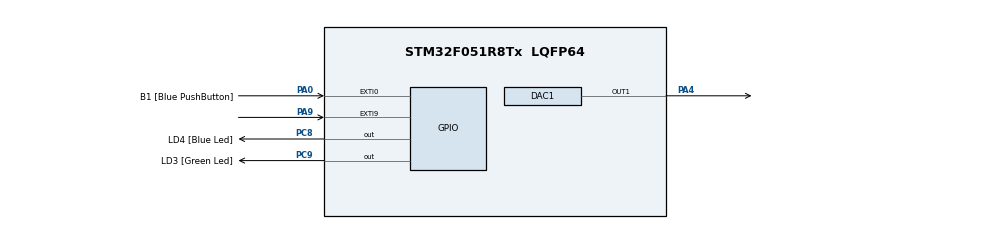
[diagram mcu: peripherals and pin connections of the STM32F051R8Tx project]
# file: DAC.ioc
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DAC1.DAC_Trigger=DAC_TRIGGER_SOFTWARE
Mcu.Family=STM32F0
Mcu.Name=STM32F051R8Tx
Mcu.Package=LQFP64
PA0.GPIO_Label=B1 [Blue PushButton]
PA0.GPIO_ModeDefaultEXTI=GPIO_MODE_EVT_RISING
PA0.Signal=GPXTI0
PA13.GPIO_Label=SWDIO
PA13.Signal=SYS_SWDIO
PA14.GPIO_Label=SWCLK
PA14.Signal=SYS_SWCLK
PA4.Signal=COMP_DAC11_group
PA9.Signal=GPXTI9
PC8.GPIO_Label=LD4 [Blue Led]
PC8.Signal=GPIO_Output
PC9.GPIO_Label=LD3 [Green Led]
PC9.Signal=GPIO_Output
ProjectManager.HeapSize=0x200
ProjectManager.StackSize=0x400
ProjectManager.TargetToolchain=MDK-ARM V5
RCC.AHBFreq_Value=48000000
RCC.APB1CLKDivider=RCC_HCLK_DIV2
RCC.APB1Freq_Value=24000000
RCC.APB1TimFreq_Value=48000000
RCC.HCLKFreq_Value=48000000
RCC.PLLMUL=RCC_PLL_MUL12
RCC.SYSCLKFreq_VALUE=48000000
RCC.SYSCLKSource=RCC_SYSCLKSOURCE_PLLCLK
SH.COMP_DAC11_group.0=DAC1_OUT1,DAC_OUT1
board=STM32F0DISCOVERY

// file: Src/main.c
/**
  ******************************************************************************
  * File Name          : main.c
  * Description        : Main program body
  ******************************************************************************
  ** This notice applies to any and all portions of this file
  * that are not between comment pairs USER CODE BEGIN and
  * USER CODE END. Other portions of this file, whether
  * inserted by the user or by software development tools
  * are owned by their respective copyright owners.
  *
  * COPYRIGHT(c) 2018 STMicroelectronics
  *
  * Redistribution and use in source and binary forms, with or without modification,
  * are permitted provided that the following conditions are met:
  *   1. Redistributions of source code must retain the above copyright notice,
  *      this list of conditions and the following disclaimer.
  *   2. Redistributions in binary form must reproduce the above copyright notice,
  *      this list of conditions and the following disclaimer in the documentation
  *      and/or other materials provided with the distribution.
  *   3. Neither the name of STMicroelectronics nor the names of its contributors
  *      may be used to endorse or promote products derived from this software
  *      without specific prior written permission.
  *
  * THIS SOFTWARE IS PROVIDED BY THE COPYRIGHT HOLDERS AND CONTRIBUTORS "AS IS"
  * AND ANY EXPRESS OR IMPLIED WARRANTIES, INCLUDING, BUT NOT LIMITED TO, THE
  * IMPLIED WARRANTIES OF MERCHANTABILITY AND FITNESS FOR A PARTICULAR PURPOSE ARE
  * DISCLAIMED. IN NO EVENT SHALL THE COPYRIGHT HOLDER OR CONTRIBUTORS BE LIABLE
  * FOR ANY DIRECT, INDIRECT, INCIDENTAL, SPECIAL, EXEMPLARY, OR CONSEQUENTIAL
  * DAMAGES (INCLUDING, BUT NOT LIMITED TO, PROCUREMENT OF SUBSTITUTE GOODS OR
  * SERVICES; LOSS OF USE, DATA, OR PROFITS; OR BUSINESS INTERRUPTION) HOWEVER
  * CAUSED AND ON ANY THEORY OF LIABILITY, WHETHER IN CONTRACT, STRICT LIABILITY,
  * OR TORT (INCLUDING NEGLIGENCE OR OTHERWISE) ARISING IN ANY WAY OUT OF THE USE
  * OF THIS SOFTWARE, EVEN IF ADVISED OF THE POSSIBILITY OF SUCH DAMAGE.
  *
  ******************************************************************************
  */

#include "main.h"
#include "stm32f0xx_hal.h"

DAC_HandleTypeDef hdac1;

/* USER CODE BEGIN PV */
/* Private variables ---------------------------------------------------------*/

/* USER CODE END PV */

void SystemClock_Config(void);
static void MX_GPIO_Init(void);
static void MX_DAC1_Init(void);

/* USER CODE BEGIN PFP */
/* Private function prototypes -----------------------------------------------*/

/* USER CODE END PFP */

int main(void)
{

  /* MCU Configuration----------------------------------------------------------*/

  /* Reset of all peripherals, Initializes the Flash interface and the Systick. */
  HAL_Init();

  /* Configure the system clock */
  SystemClock_Config();

  /* Initialize all configured peripherals */
  MX_GPIO_Init();
  MX_DAC1_Init();

  /* Infinite loop */
  while (1)
  {
		for(int i=0; i< 2048; i++){
			HAL_DAC_Start(&hdac1, DAC_CHANNEL_1);
			HAL_DAC_SetValue(&hdac1, DAC_CHANNEL_1, DAC_ALIGN_12B_R, (i*2)+1);
			//HAL_DAC_Stop(&hdac1, DAC_CHANNEL_1);
		}
		for(int i=2048; i > 0; i--){
			HAL_DAC_Start(&hdac1, DAC_CHANNEL_1);
			HAL_DAC_SetValue(&hdac1, DAC_CHANNEL_1, DAC_ALIGN_12B_R, (i*2)+1);
			//HAL_DAC_Stop(&hdac1, DAC_CHANNEL_1);
		}
		HAL_GPIO_TogglePin(GPIOC, GPIO_PIN_8);
		//HAL_DACEx_TriangleWaveGenerate(&hdac1, DAC_CHANNEL_1, DAC_ALIGN_12B_R);
  }

}

/** System Clock Configuration
*/
void SystemClock_Config(void)
{

  RCC_OscInitTypeDef RCC_OscInitStruct;
  RCC_ClkInitTypeDef RCC_ClkInitStruct;

    /**Initializes the CPU, AHB and APB busses clocks
    */
  RCC_OscInitStruct.OscillatorType = RCC_OSCILLATORTYPE_HSI;
  RCC_OscInitStruct.HSIState = RCC_HSI_ON;
  RCC_OscInitStruct.HSICalibrationValue = 16;
  RCC_OscInitStruct.PLL.PLLState = RCC_PLL_ON;
  RCC_OscInitStruct.PLL.PLLSource = RCC_PLLSOURCE_HSI;
  RCC_OscInitStruct.PLL.PLLMUL = RCC_PLL_MUL12;
  RCC_OscInitStruct.PLL.PREDIV = RCC_PREDIV_DIV1;
  if (HAL_RCC_OscConfig(&RCC_OscInitStruct) != HAL_OK)
  {
    _Error_Handler(__FILE__, __LINE__);
  }

    /**Initializes the CPU, AHB and APB busses clocks
    */
  RCC_ClkInitStruct.ClockType = RCC_CLOCKTYPE_HCLK|RCC_CLOCKTYPE_SYSCLK
                              |RCC_CLOCKTYPE_PCLK1;
  RCC_ClkInitStruct.SYSCLKSource = RCC_SYSCLKSOURCE_PLLCLK;
  RCC_ClkInitStruct.AHBCLKDivider = RCC_SYSCLK_DIV1;
  RCC_ClkInitStruct.APB1CLKDivider = RCC_HCLK_DIV1;

  if (HAL_RCC_ClockConfig(&RCC_ClkInitStruct, FLASH_LATENCY_1) != HAL_OK)
  {
    _Error_Handler(__FILE__, __LINE__);
  }

    /**Configure the Systick interrupt time
    */
  HAL_SYSTICK_Config(HAL_RCC_GetHCLKFreq()/1000);

    /**Configure the Systick
    */
  HAL_SYSTICK_CLKSourceConfig(SYSTICK_CLKSOURCE_HCLK);

  /* SysTick_IRQn interrupt configuration */
  HAL_NVIC_SetPriority(SysTick_IRQn, 0, 0);
}

/* DAC1 init function */
static void MX_DAC1_Init(void)
{

  DAC_ChannelConfTypeDef sConfig;

    /**DAC Initialization
    */
  hdac1.Instance = DAC;
  if (HAL_DAC_Init(&hdac1) != HAL_OK)
  {
    _Error_Handler(__FILE__, __LINE__);
  }

    /**DAC channel OUT1 config
    */
  sConfig.DAC_Trigger = DAC_TRIGGER_NONE;
  sConfig.DAC_OutputBuffer = DAC_OUTPUTBUFFER_ENABLE;
  if (HAL_DAC_ConfigChannel(&hdac1, &sConfig, DAC_CHANNEL_1) != HAL_OK)
  {
    _Error_Handler(__FILE__, __LINE__);
  }

}

/** Configure pins as
        * Analog
        * Input
        * Output
        * EVENT_OUT
        * EXTI
*/
static void MX_GPIO_Init(void)
{

  GPIO_InitTypeDef GPIO_InitStruct;

  /* GPIO Ports Clock Enable */
  __HAL_RCC_GPIOA_CLK_ENABLE();
  __HAL_RCC_GPIOC_CLK_ENABLE();

  /*Configure GPIO pin Output Level */
  HAL_GPIO_WritePin(GPIOC, LD4_Pin|LD3_Pin, GPIO_PIN_RESET);

  /*Configure GPIO pin : B1_Pin */
  GPIO_InitStruct.Pin = B1_Pin;
  GPIO_InitStruct.Mode = GPIO_MODE_EVT_RISING;
  GPIO_InitStruct.Pull = GPIO_NOPULL;
  HAL_GPIO_Init(B1_GPIO_Port, &GPIO_InitStruct);

  /*Configure GPIO pins : LD4_Pin LD3_Pin */
  GPIO_InitStruct.Pin = LD4_Pin|LD3_Pin;
  GPIO_InitStruct.Mode = GPIO_MODE_OUTPUT_PP;
  GPIO_InitStruct.Pull = GPIO_NOPULL;
  GPIO_InitStruct.Speed = GPIO_SPEED_FREQ_LOW;
  HAL_GPIO_Init(GPIOC, &GPIO_InitStruct);

  /*Configure GPIO pin : PA9 */
  GPIO_InitStruct.Pin = GPIO_PIN_9;
  GPIO_InitStruct.Mode = GPIO_MODE_IT_RISING;
  GPIO_InitStruct.Pull = GPIO_NOPULL;
  HAL_GPIO_Init(GPIOA, &GPIO_InitStruct);

}

void _Error_Handler(char * file, int line)
{
  while(1)
  {
  }
}

/************************ (C) COPYRIGHT STMicroelectronics *****END OF FILE****/
